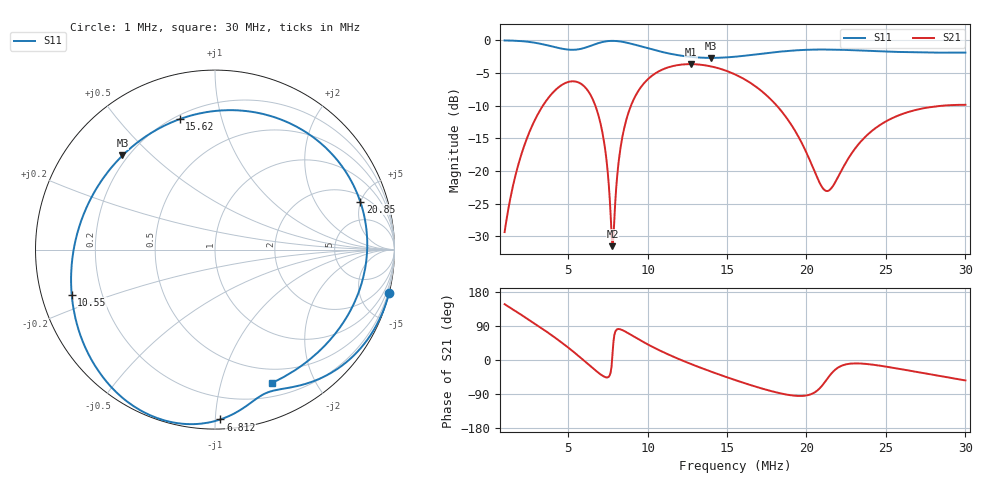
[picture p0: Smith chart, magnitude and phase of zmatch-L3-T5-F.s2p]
# HZ S RI R 50
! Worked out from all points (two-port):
!   505 points, 1 MHz to 30 MHz, reference 50 ohm
!   highest |S21| = -3.63 dB at 12.74 MHz (marker M1); lowest = -31.5 dB at 7.79 MHz (marker M2)
!   |S21| within 3 dB of the highest: 4.733 MHz to 5.802 MHz (1.069 MHz wide, 20.3 % of centre); 9.747 MHz to 16.55 MHz (6.804 MHz wide, 51.7 % of centre)
!   lowest |S11| = -2.7 dB at 14 MHz (marker M3), VSWR 6.55, Z = 8.93 + j20.4 ohm
!   |S11| at or under -10 dB: nowhere
!   S12 and S22 are empty: the file has one direction only
!   S11 on the Smith chart (normalised r, x): 1 MHz: 0.00, -8.20; 6.812 MHz: 0.06, -1.03; 10.55 MHz: 0.09, -0.15; 15.62 MHz: 0.22, +0.74; 20.85 MHz: 2.53, +4.95; 30 MHz: 0.34, -1.46
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1000000  0.9706 -0.2402  -0.0287 0.0184  0 0  0 0
1920640  0.8816 -0.4529  -0.0639 0.0998  0 0  0 0
3071440  0.6836 -0.6637  -0.00521 0.2694  0 0  0 0
4452400  0.4114 -0.7697  0.2823 0.3419  0 0  0 0
5833360  0.2261 -0.834  0.4623 0.0342  0 0  0 0
6811540  0.0306 -0.9462  0.2508 -0.1488  0 0  0 0
7329400  -0.1381 -0.9725  0.1032 -0.1035  0 0  0 0
7789720  -0.3023 -0.9453  0.0258 0.00657  0 0  0 0
8192500  -0.4357 -0.8834  0.0175 0.1207  0 0  0 0
8652820  -0.5627 -0.7818  0.0688 0.2356  0 0  0 0
1.055164e7  -0.7983 -0.2516  0.4928 0.2788  0 0  0 0
1.066672e7  -0.8006 -0.2199  0.5137 0.263  0 0  0 0
1.273816e7  -0.6915 0.2849  0.6471 -0.1225  0 0  0 0
1.400404e7  -0.5154 0.5243  0.5431 -0.3239  0 0  0 0
1.550008e7  -0.2225 0.7171  0.3323 -0.4378  0 0  0 0
1.561516e7  -0.1968 0.7269  0.3151 -0.4403  0 0  0 0
1.780168e7  0.3238 0.74  0.0468 -0.3462  0 0  0 0
2.033344e7  0.766 0.3692  0.00123 -0.1115  0 0  0 0
2.08513e7  0.8091 0.2678  0.0223 -0.077  0 0  0 0
2.148424e7  0.8395 0.1437  0.0554 -0.0462  0 0  0 0
2.51668e7  0.7077 -0.4171  0.2333 -0.0786  0 0  0 0
3.000016e7  0.315 -0.7436  0.1893 -0.2598  0 0  0 0
